VERSION 5.7 ;
  NOWIREEXTENSIONATPIN ON ;
  DIVIDERCHAR "/" ;
  BUSBITCHARS "[]" ;
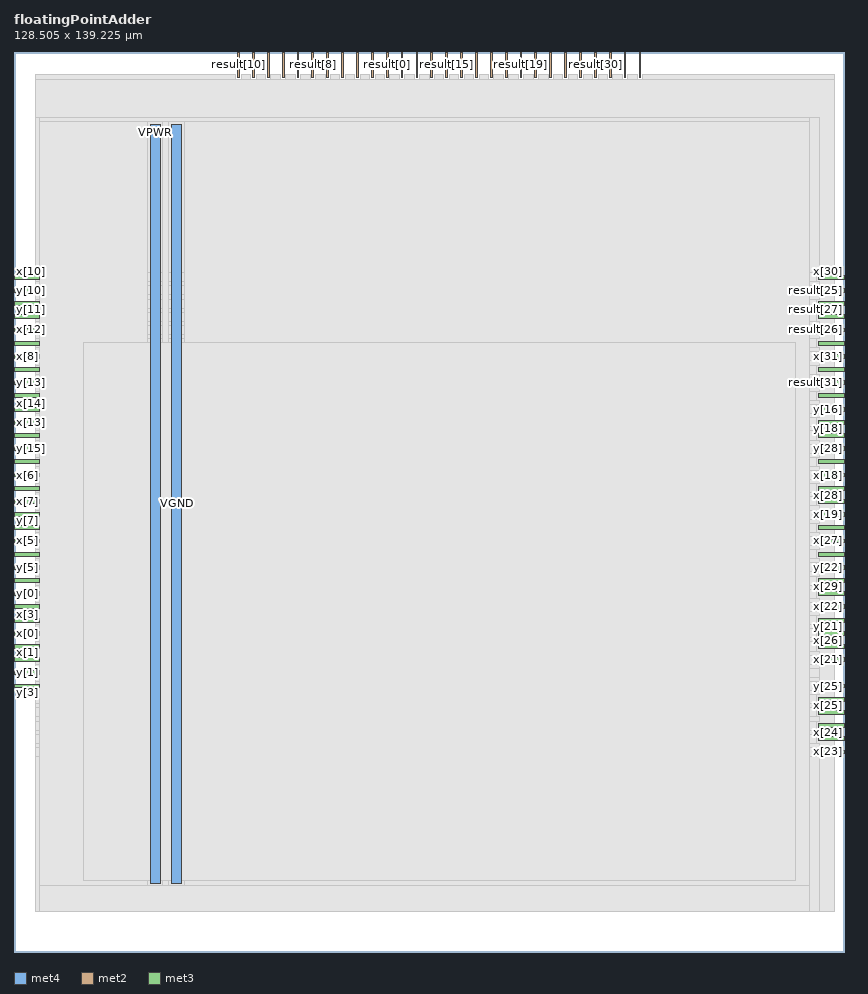
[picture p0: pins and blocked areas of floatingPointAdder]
MACRO floatingPointAdder
  CLASS BLOCK ;
  FOREIGN floatingPointAdder ;
  ORIGIN 0.000 0.000 ;
  SIZE 128.505 BY 139.225 ;
  PIN VGND
    DIRECTION INOUT ;
    USE GROUND ;
    PORT
      LAYER met4 ;
        RECT 24.340 10.640 25.940 128.080 ;
    END
  END VGND
  PIN VPWR
    DIRECTION INOUT ;
    USE POWER ;
    PORT
      LAYER met4 ;
        RECT 21.040 10.640 22.640 128.080 ;
    END
  END VPWR
  PIN result[0]
    DIRECTION OUTPUT ;
    USE SIGNAL ;
    ANTENNADIFFAREA 0.340600 ;
    PORT
      LAYER met2 ;
        RECT 57.590 135.225 57.870 139.225 ;
    END
  END result[0]
  PIN result[10]
    DIRECTION OUTPUT ;
    USE SIGNAL ;
    ANTENNADIFFAREA 0.340600 ;
    PORT
      LAYER met2 ;
        RECT 34.590 135.225 34.870 139.225 ;
    END
  END result[10]
  PIN result[11]
    DIRECTION OUTPUT ;
    USE SIGNAL ;
    ANTENNADIFFAREA 0.340600 ;
    PORT
      LAYER met2 ;
        RECT 43.790 135.225 44.070 139.225 ;
    END
  END result[11]
  PIN result[12]
    DIRECTION OUTPUT ;
    USE SIGNAL ;
    ANTENNADIFFAREA 0.340600 ;
    PORT
      LAYER met2 ;
        RECT 55.290 135.225 55.570 139.225 ;
    END
  END result[12]
  PIN result[13]
    DIRECTION OUTPUT ;
    USE SIGNAL ;
    ANTENNADIFFAREA 0.340600 ;
    PORT
      LAYER met2 ;
        RECT 52.990 135.225 53.270 139.225 ;
    END
  END result[13]
  PIN result[14]
    DIRECTION OUTPUT ;
    USE SIGNAL ;
    ANTENNADIFFAREA 0.340600 ;
    PORT
      LAYER met2 ;
        RECT 69.090 135.225 69.370 139.225 ;
    END
  END result[14]
  PIN result[15]
    DIRECTION OUTPUT ;
    USE SIGNAL ;
    ANTENNADIFFAREA 0.340600 ;
    PORT
      LAYER met2 ;
        RECT 66.790 135.225 67.070 139.225 ;
    END
  END result[15]
  PIN result[16]
    DIRECTION OUTPUT ;
    USE SIGNAL ;
    ANTENNADIFFAREA 0.340600 ;
    PORT
      LAYER met2 ;
        RECT 87.490 135.225 87.770 139.225 ;
    END
  END result[16]
  PIN result[17]
    DIRECTION OUTPUT ;
    USE SIGNAL ;
    ANTENNADIFFAREA 0.340600 ;
    PORT
      LAYER met2 ;
        RECT 73.690 135.225 73.970 139.225 ;
    END
  END result[17]
  PIN result[18]
    DIRECTION OUTPUT ;
    USE SIGNAL ;
    ANTENNADIFFAREA 0.340600 ;
    PORT
      LAYER met2 ;
        RECT 85.190 135.225 85.470 139.225 ;
    END
  END result[18]
  PIN result[19]
    DIRECTION OUTPUT ;
    USE SIGNAL ;
    ANTENNADIFFAREA 0.340600 ;
    PORT
      LAYER met2 ;
        RECT 78.290 135.225 78.570 139.225 ;
    END
  END result[19]
  PIN result[1]
    DIRECTION OUTPUT ;
    USE SIGNAL ;
    ANTENNADIFFAREA 0.340600 ;
    PORT
      LAYER met2 ;
        RECT 64.490 135.225 64.770 139.225 ;
    END
  END result[1]
  PIN result[20]
    DIRECTION OUTPUT ;
    USE SIGNAL ;
    ANTENNADIFFAREA 0.340600 ;
    PORT
      LAYER met2 ;
        RECT 80.590 135.225 80.870 139.225 ;
    END
  END result[20]
  PIN result[21]
    DIRECTION OUTPUT ;
    USE SIGNAL ;
    ANTENNADIFFAREA 0.340600 ;
    PORT
      LAYER met2 ;
        RECT 82.890 135.225 83.170 139.225 ;
    END
  END result[21]
  PIN result[22]
    DIRECTION OUTPUT ;
    USE SIGNAL ;
    ANTENNADIFFAREA 0.340600 ;
    PORT
      LAYER met2 ;
        RECT 92.090 135.225 92.370 139.225 ;
    END
  END result[22]
  PIN result[23]
    DIRECTION OUTPUT ;
    USE SIGNAL ;
    ANTENNADIFFAREA 0.340600 ;
    PORT
      LAYER met3 ;
        RECT 124.505 93.880 128.505 94.480 ;
    END
  END result[23]
  PIN result[24]
    DIRECTION OUTPUT ;
    USE SIGNAL ;
    ANTENNADIFFAREA 0.340600 ;
    PORT
      LAYER met3 ;
        RECT 124.505 89.800 128.505 90.400 ;
    END
  END result[24]
  PIN result[25]
    DIRECTION OUTPUT ;
    USE SIGNAL ;
    ANTENNADIFFAREA 0.340600 ;
    PORT
      LAYER met3 ;
        RECT 124.505 102.040 128.505 102.640 ;
    END
  END result[25]
  PIN result[26]
    DIRECTION OUTPUT ;
    USE SIGNAL ;
    ANTENNADIFFAREA 0.340600 ;
    PORT
      LAYER met3 ;
        RECT 124.505 95.920 128.505 96.520 ;
    END
  END result[26]
  PIN result[27]
    DIRECTION OUTPUT ;
    USE SIGNAL ;
    ANTENNADIFFAREA 0.340600 ;
    PORT
      LAYER met3 ;
        RECT 124.505 100.000 128.505 100.600 ;
    END
  END result[27]
  PIN result[28]
    DIRECTION OUTPUT ;
    USE SIGNAL ;
    ANTENNADIFFAREA 0.340600 ;
    PORT
      LAYER met2 ;
        RECT 96.690 135.225 96.970 139.225 ;
    END
  END result[28]
  PIN result[29]
    DIRECTION OUTPUT ;
    USE SIGNAL ;
    ANTENNADIFFAREA 0.340600 ;
    PORT
      LAYER met2 ;
        RECT 94.390 135.225 94.670 139.225 ;
    END
  END result[29]
  PIN result[2]
    DIRECTION OUTPUT ;
    USE SIGNAL ;
    ANTENNADIFFAREA 0.340600 ;
    PORT
      LAYER met2 ;
        RECT 59.890 135.225 60.170 139.225 ;
    END
  END result[2]
  PIN result[30]
    DIRECTION OUTPUT ;
    USE SIGNAL ;
    ANTENNADIFFAREA 0.340600 ;
    PORT
      LAYER met2 ;
        RECT 89.790 135.225 90.070 139.225 ;
    END
  END result[30]
  PIN result[31]
    DIRECTION OUTPUT ;
    USE SIGNAL ;
    ANTENNADIFFAREA 0.340600 ;
    PORT
      LAYER met3 ;
        RECT 124.505 87.760 128.505 88.360 ;
    END
  END result[31]
  PIN result[3]
    DIRECTION OUTPUT ;
    USE SIGNAL ;
    ANTENNADIFFAREA 0.340600 ;
    PORT
      LAYER met2 ;
        RECT 36.890 135.225 37.170 139.225 ;
    END
  END result[3]
  PIN result[4]
    DIRECTION OUTPUT ;
    USE SIGNAL ;
    ANTENNADIFFAREA 0.340600 ;
    PORT
      LAYER met2 ;
        RECT 39.190 135.225 39.470 139.225 ;
    END
  END result[4]
  PIN result[5]
    DIRECTION OUTPUT ;
    USE SIGNAL ;
    ANTENNADIFFAREA 0.340600 ;
    PORT
      LAYER met2 ;
        RECT 50.690 135.225 50.970 139.225 ;
    END
  END result[5]
  PIN result[6]
    DIRECTION OUTPUT ;
    USE SIGNAL ;
    ANTENNADIFFAREA 0.340600 ;
    PORT
      LAYER met2 ;
        RECT 62.190 135.225 62.470 139.225 ;
    END
  END result[6]
  PIN result[7]
    DIRECTION OUTPUT ;
    USE SIGNAL ;
    ANTENNADIFFAREA 0.340600 ;
    PORT
      LAYER met2 ;
        RECT 48.390 135.225 48.670 139.225 ;
    END
  END result[7]
  PIN result[8]
    DIRECTION OUTPUT ;
    USE SIGNAL ;
    ANTENNADIFFAREA 0.340600 ;
    PORT
      LAYER met2 ;
        RECT 46.090 135.225 46.370 139.225 ;
    END
  END result[8]
  PIN result[9]
    DIRECTION OUTPUT ;
    USE SIGNAL ;
    ANTENNADIFFAREA 0.340600 ;
    PORT
      LAYER met2 ;
        RECT 41.490 135.225 41.770 139.225 ;
    END
  END result[9]
  PIN x[0]
    DIRECTION INPUT ;
    USE SIGNAL ;
    ANTENNAGATEAREA 0.196500 ;
    PORT
      LAYER met3 ;
        RECT 0.000 49.000 4.000 49.600 ;
    END
  END x[0]
  PIN x[10]
    DIRECTION INPUT ;
    USE SIGNAL ;
    ANTENNAGATEAREA 0.196500 ;
    PORT
      LAYER met3 ;
        RECT 0.000 104.080 4.000 104.680 ;
    END
  END x[10]
  PIN x[11]
    DIRECTION INPUT ;
    USE SIGNAL ;
    ANTENNAGATEAREA 0.213000 ;
    PORT
      LAYER met3 ;
        RECT 0.000 97.960 4.000 98.560 ;
    END
  END x[11]
  PIN x[12]
    DIRECTION INPUT ;
    USE SIGNAL ;
    ANTENNAGATEAREA 0.213000 ;
    PORT
      LAYER met3 ;
        RECT 0.000 95.920 4.000 96.520 ;
    END
  END x[12]
  PIN x[13]
    DIRECTION INPUT ;
    USE SIGNAL ;
    ANTENNAGATEAREA 0.196500 ;
    PORT
      LAYER met3 ;
        RECT 0.000 81.640 4.000 82.240 ;
    END
  END x[13]
  PIN x[14]
    DIRECTION INPUT ;
    USE SIGNAL ;
    ANTENNAGATEAREA 0.196500 ;
    PORT
      LAYER met3 ;
        RECT 0.000 83.680 4.000 84.280 ;
    END
  END x[14]
  PIN x[15]
    DIRECTION INPUT ;
    USE SIGNAL ;
    ANTENNAGATEAREA 0.213000 ;
    PORT
      LAYER met3 ;
        RECT 0.000 75.520 4.000 76.120 ;
    END
  END x[15]
  PIN x[16]
    DIRECTION INPUT ;
    USE SIGNAL ;
    ANTENNAGATEAREA 0.159000 ;
    PORT
      LAYER met2 ;
        RECT 71.390 135.225 71.670 139.225 ;
    END
  END x[16]
  PIN x[17]
    DIRECTION INPUT ;
    USE SIGNAL ;
    ANTENNAGATEAREA 0.631200 ;
    ANTENNADIFFAREA 0.434700 ;
    PORT
      LAYER met3 ;
        RECT 124.505 75.520 128.505 76.120 ;
    END
  END x[17]
  PIN x[18]
    DIRECTION INPUT ;
    USE SIGNAL ;
    ANTENNAGATEAREA 1.065900 ;
    ANTENNADIFFAREA 0.869400 ;
    PORT
      LAYER met3 ;
        RECT 124.505 73.480 128.505 74.080 ;
    END
  END x[18]
  PIN x[19]
    DIRECTION INPUT ;
    USE SIGNAL ;
    ANTENNAGATEAREA 0.593700 ;
    ANTENNADIFFAREA 0.434700 ;
    PORT
      LAYER met3 ;
        RECT 124.505 67.360 128.505 67.960 ;
    END
  END x[19]
  PIN x[1]
    DIRECTION INPUT ;
    USE SIGNAL ;
    ANTENNAGATEAREA 0.196500 ;
    PORT
      LAYER met3 ;
        RECT 0.000 46.960 4.000 47.560 ;
    END
  END x[1]
  PIN x[20]
    DIRECTION INPUT ;
    USE SIGNAL ;
    ANTENNAGATEAREA 0.196500 ;
    PORT
      LAYER met3 ;
        RECT 124.505 71.440 128.505 72.040 ;
    END
  END x[20]
  PIN x[21]
    DIRECTION INPUT ;
    USE SIGNAL ;
    ANTENNAGATEAREA 0.631200 ;
    ANTENNADIFFAREA 0.434700 ;
    PORT
      LAYER met3 ;
        RECT 124.505 44.920 128.505 45.520 ;
    END
  END x[21]
  PIN x[22]
    DIRECTION INPUT ;
    USE SIGNAL ;
    ANTENNAGATEAREA 0.631200 ;
    ANTENNADIFFAREA 0.434700 ;
    PORT
      LAYER met3 ;
        RECT 124.505 53.080 128.505 53.680 ;
    END
  END x[22]
  PIN x[23]
    DIRECTION INPUT ;
    USE SIGNAL ;
    ANTENNAGATEAREA 0.213000 ;
    PORT
      LAYER met3 ;
        RECT 124.505 30.640 128.505 31.240 ;
    END
  END x[23]
  PIN x[24]
    DIRECTION INPUT ;
    USE SIGNAL ;
    ANTENNAGATEAREA 0.159000 ;
    PORT
      LAYER met3 ;
        RECT 124.505 32.680 128.505 33.280 ;
    END
  END x[24]
  PIN x[25]
    DIRECTION INPUT ;
    USE SIGNAL ;
    ANTENNAGATEAREA 0.213000 ;
    PORT
      LAYER met3 ;
        RECT 124.505 38.800 128.505 39.400 ;
    END
  END x[25]
  PIN x[26]
    DIRECTION INPUT ;
    USE SIGNAL ;
    ANTENNAGATEAREA 0.159000 ;
    PORT
      LAYER met3 ;
        RECT 124.505 46.960 128.505 47.560 ;
    END
  END x[26]
  PIN x[27]
    DIRECTION INPUT ;
    USE SIGNAL ;
    ANTENNAGATEAREA 0.159000 ;
    PORT
      LAYER met3 ;
        RECT 124.505 63.280 128.505 63.880 ;
    END
  END x[27]
  PIN x[28]
    DIRECTION INPUT ;
    USE SIGNAL ;
    ANTENNAGATEAREA 0.213000 ;
    PORT
      LAYER met3 ;
        RECT 124.505 69.400 128.505 70.000 ;
    END
  END x[28]
  PIN x[29]
    DIRECTION INPUT ;
    USE SIGNAL ;
    ANTENNAGATEAREA 0.426000 ;
    PORT
      LAYER met3 ;
        RECT 124.505 57.160 128.505 57.760 ;
    END
  END x[29]
  PIN x[2]
    DIRECTION INPUT ;
    USE SIGNAL ;
    ANTENNAGATEAREA 0.126000 ;
    PORT
      LAYER met3 ;
        RECT 0.000 44.920 4.000 45.520 ;
    END
  END x[2]
  PIN x[30]
    DIRECTION INPUT ;
    USE SIGNAL ;
    ANTENNAGATEAREA 0.213000 ;
    PORT
      LAYER met3 ;
        RECT 124.505 104.080 128.505 104.680 ;
    END
  END x[30]
  PIN x[31]
    DIRECTION INPUT ;
    USE SIGNAL ;
    ANTENNAGATEAREA 0.213000 ;
    PORT
      LAYER met3 ;
        RECT 124.505 91.840 128.505 92.440 ;
    END
  END x[31]
  PIN x[3]
    DIRECTION INPUT ;
    USE SIGNAL ;
    ANTENNAGATEAREA 0.196500 ;
    PORT
      LAYER met3 ;
        RECT 0.000 51.040 4.000 51.640 ;
    END
  END x[3]
  PIN x[4]
    DIRECTION INPUT ;
    USE SIGNAL ;
    ANTENNAGATEAREA 0.126000 ;
    PORT
      LAYER met3 ;
        RECT 0.000 65.320 4.000 65.920 ;
    END
  END x[4]
  PIN x[5]
    DIRECTION INPUT ;
    USE SIGNAL ;
    ANTENNAGATEAREA 0.213000 ;
    PORT
      LAYER met3 ;
        RECT 0.000 63.280 4.000 63.880 ;
    END
  END x[5]
  PIN x[6]
    DIRECTION INPUT ;
    USE SIGNAL ;
    ANTENNAGATEAREA 0.213000 ;
    PORT
      LAYER met3 ;
        RECT 0.000 73.480 4.000 74.080 ;
    END
  END x[6]
  PIN x[7]
    DIRECTION INPUT ;
    USE SIGNAL ;
    ANTENNAGATEAREA 0.196500 ;
    PORT
      LAYER met3 ;
        RECT 0.000 69.400 4.000 70.000 ;
    END
  END x[7]
  PIN x[8]
    DIRECTION INPUT ;
    USE SIGNAL ;
    ANTENNAGATEAREA 0.196500 ;
    PORT
      LAYER met3 ;
        RECT 0.000 91.840 4.000 92.440 ;
    END
  END x[8]
  PIN x[9]
    DIRECTION INPUT ;
    USE SIGNAL ;
    ANTENNAGATEAREA 0.196500 ;
    PORT
      LAYER met3 ;
        RECT 0.000 93.880 4.000 94.480 ;
    END
  END x[9]
  PIN y[0]
    DIRECTION INPUT ;
    USE SIGNAL ;
    ANTENNAGATEAREA 0.126000 ;
    PORT
      LAYER met3 ;
        RECT 0.000 55.120 4.000 55.720 ;
    END
  END y[0]
  PIN y[10]
    DIRECTION INPUT ;
    USE SIGNAL ;
    ANTENNAGATEAREA 0.126000 ;
    PORT
      LAYER met3 ;
        RECT 0.000 102.040 4.000 102.640 ;
    END
  END y[10]
  PIN y[11]
    DIRECTION INPUT ;
    USE SIGNAL ;
    ANTENNAGATEAREA 0.126000 ;
    PORT
      LAYER met3 ;
        RECT 0.000 100.000 4.000 100.600 ;
    END
  END y[11]
  PIN y[12]
    DIRECTION INPUT ;
    USE SIGNAL ;
    ANTENNAGATEAREA 0.213000 ;
    PORT
      LAYER met3 ;
        RECT 0.000 79.600 4.000 80.200 ;
    END
  END y[12]
  PIN y[13]
    DIRECTION INPUT ;
    USE SIGNAL ;
    ANTENNAGATEAREA 0.126000 ;
    PORT
      LAYER met3 ;
        RECT 0.000 87.760 4.000 88.360 ;
    END
  END y[13]
  PIN y[14]
    DIRECTION INPUT ;
    USE SIGNAL ;
    ANTENNAGATEAREA 0.196500 ;
    PORT
      LAYER met3 ;
        RECT 0.000 85.720 4.000 86.320 ;
    END
  END y[14]
  PIN y[15]
    DIRECTION INPUT ;
    USE SIGNAL ;
    ANTENNAGATEAREA 0.213000 ;
    PORT
      LAYER met3 ;
        RECT 0.000 77.560 4.000 78.160 ;
    END
  END y[15]
  PIN y[16]
    DIRECTION INPUT ;
    USE SIGNAL ;
    ANTENNAGATEAREA 0.213000 ;
    PORT
      LAYER met3 ;
        RECT 124.505 83.680 128.505 84.280 ;
    END
  END y[16]
  PIN y[17]
    DIRECTION INPUT ;
    USE SIGNAL ;
    ANTENNAGATEAREA 0.159000 ;
    PORT
      LAYER met2 ;
        RECT 75.990 135.225 76.270 139.225 ;
    END
  END y[17]
  PIN y[18]
    DIRECTION INPUT ;
    USE SIGNAL ;
    ANTENNAGATEAREA 0.159000 ;
    PORT
      LAYER met3 ;
        RECT 124.505 81.640 128.505 82.240 ;
    END
  END y[18]
  PIN y[19]
    DIRECTION INPUT ;
    USE SIGNAL ;
    ANTENNAGATEAREA 0.213000 ;
    PORT
      LAYER met3 ;
        RECT 124.505 65.320 128.505 65.920 ;
    END
  END y[19]
  PIN y[1]
    DIRECTION INPUT ;
    USE SIGNAL ;
    ANTENNAGATEAREA 0.213000 ;
    PORT
      LAYER met3 ;
        RECT 0.000 42.880 4.000 43.480 ;
    END
  END y[1]
  PIN y[20]
    DIRECTION INPUT ;
    USE SIGNAL ;
    ANTENNAGATEAREA 0.213000 ;
    PORT
      LAYER met3 ;
        RECT 124.505 79.600 128.505 80.200 ;
    END
  END y[20]
  PIN y[21]
    DIRECTION INPUT ;
    USE SIGNAL ;
    ANTENNAGATEAREA 0.159000 ;
    PORT
      LAYER met3 ;
        RECT 124.505 51.040 128.505 51.640 ;
    END
  END y[21]
  PIN y[22]
    DIRECTION INPUT ;
    USE SIGNAL ;
    ANTENNAGATEAREA 0.213000 ;
    PORT
      LAYER met3 ;
        RECT 124.505 59.200 128.505 59.800 ;
    END
  END y[22]
  PIN y[23]
    DIRECTION INPUT ;
    USE SIGNAL ;
    ANTENNAGATEAREA 0.213000 ;
    PORT
      LAYER met3 ;
        RECT 124.505 34.720 128.505 35.320 ;
    END
  END y[23]
  PIN y[24]
    DIRECTION INPUT ;
    USE SIGNAL ;
    ANTENNAGATEAREA 0.213000 ;
    PORT
      LAYER met3 ;
        RECT 124.505 36.760 128.505 37.360 ;
    END
  END y[24]
  PIN y[25]
    DIRECTION INPUT ;
    USE SIGNAL ;
    ANTENNAGATEAREA 0.247500 ;
    PORT
      LAYER met3 ;
        RECT 124.505 40.840 128.505 41.440 ;
    END
  END y[25]
  PIN y[26]
    DIRECTION INPUT ;
    USE SIGNAL ;
    ANTENNAGATEAREA 0.213000 ;
    PORT
      LAYER met3 ;
        RECT 124.505 49.000 128.505 49.600 ;
    END
  END y[26]
  PIN y[27]
    DIRECTION INPUT ;
    USE SIGNAL ;
    ANTENNAGATEAREA 0.213000 ;
    PORT
      LAYER met3 ;
        RECT 124.505 61.240 128.505 61.840 ;
    END
  END y[27]
  PIN y[28]
    DIRECTION INPUT ;
    USE SIGNAL ;
    ANTENNAGATEAREA 0.213000 ;
    PORT
      LAYER met3 ;
        RECT 124.505 77.560 128.505 78.160 ;
    END
  END y[28]
  PIN y[29]
    DIRECTION INPUT ;
    USE SIGNAL ;
    ANTENNAGATEAREA 0.213000 ;
    PORT
      LAYER met3 ;
        RECT 124.505 55.120 128.505 55.720 ;
    END
  END y[29]
  PIN y[2]
    DIRECTION INPUT ;
    USE SIGNAL ;
    ANTENNAGATEAREA 0.213000 ;
    PORT
      LAYER met3 ;
        RECT 0.000 53.080 4.000 53.680 ;
    END
  END y[2]
  PIN y[30]
    DIRECTION INPUT ;
    USE SIGNAL ;
    ANTENNAGATEAREA 0.213000 ;
    PORT
      LAYER met3 ;
        RECT 124.505 97.960 128.505 98.560 ;
    END
  END y[30]
  PIN y[31]
    DIRECTION INPUT ;
    USE SIGNAL ;
    ANTENNAGATEAREA 0.213000 ;
    PORT
      LAYER met3 ;
        RECT 124.505 85.720 128.505 86.320 ;
    END
  END y[31]
  PIN y[3]
    DIRECTION INPUT ;
    USE SIGNAL ;
    ANTENNAGATEAREA 0.196500 ;
    PORT
      LAYER met3 ;
        RECT 0.000 40.840 4.000 41.440 ;
    END
  END y[3]
  PIN y[4]
    DIRECTION INPUT ;
    USE SIGNAL ;
    ANTENNAGATEAREA 0.213000 ;
    PORT
      LAYER met3 ;
        RECT 0.000 57.160 4.000 57.760 ;
    END
  END y[4]
  PIN y[5]
    DIRECTION INPUT ;
    USE SIGNAL ;
    ANTENNAGATEAREA 0.126000 ;
    PORT
      LAYER met3 ;
        RECT 0.000 59.200 4.000 59.800 ;
    END
  END y[5]
  PIN y[6]
    DIRECTION INPUT ;
    USE SIGNAL ;
    ANTENNAGATEAREA 0.196500 ;
    PORT
      LAYER met3 ;
        RECT 0.000 71.440 4.000 72.040 ;
    END
  END y[6]
  PIN y[7]
    DIRECTION INPUT ;
    USE SIGNAL ;
    ANTENNAGATEAREA 0.213000 ;
    PORT
      LAYER met3 ;
        RECT 0.000 67.360 4.000 67.960 ;
    END
  END y[7]
  PIN y[8]
    DIRECTION INPUT ;
    USE SIGNAL ;
    ANTENNAGATEAREA 0.126000 ;
    PORT
      LAYER met3 ;
        RECT 0.000 89.800 4.000 90.400 ;
    END
  END y[8]
  PIN y[9]
    DIRECTION INPUT ;
    USE SIGNAL ;
    ANTENNAGATEAREA 0.213000 ;
    PORT
      LAYER met3 ;
        RECT 0.000 61.240 4.000 61.840 ;
    END
  END y[9]
  OBS
      LAYER nwell ;
        RECT 5.330 10.795 123.010 128.030 ;
      LAYER li1 ;
        RECT 5.520 10.795 122.820 127.925 ;
      LAYER met1 ;
        RECT 3.290 9.560 126.890 132.220 ;
      LAYER met2 ;
        RECT 3.310 134.945 34.310 135.730 ;
        RECT 35.150 134.945 36.610 135.730 ;
        RECT 37.450 134.945 38.910 135.730 ;
        RECT 39.750 134.945 41.210 135.730 ;
        RECT 42.050 134.945 43.510 135.730 ;
        RECT 44.350 134.945 45.810 135.730 ;
        RECT 46.650 134.945 48.110 135.730 ;
        RECT 48.950 134.945 50.410 135.730 ;
        RECT 51.250 134.945 52.710 135.730 ;
        RECT 53.550 134.945 55.010 135.730 ;
        RECT 55.850 134.945 57.310 135.730 ;
        RECT 58.150 134.945 59.610 135.730 ;
        RECT 60.450 134.945 61.910 135.730 ;
        RECT 62.750 134.945 64.210 135.730 ;
        RECT 65.050 134.945 66.510 135.730 ;
        RECT 67.350 134.945 68.810 135.730 ;
        RECT 69.650 134.945 71.110 135.730 ;
        RECT 71.950 134.945 73.410 135.730 ;
        RECT 74.250 134.945 75.710 135.730 ;
        RECT 76.550 134.945 78.010 135.730 ;
        RECT 78.850 134.945 80.310 135.730 ;
        RECT 81.150 134.945 82.610 135.730 ;
        RECT 83.450 134.945 84.910 135.730 ;
        RECT 85.750 134.945 87.210 135.730 ;
        RECT 88.050 134.945 89.510 135.730 ;
        RECT 90.350 134.945 91.810 135.730 ;
        RECT 92.650 134.945 94.110 135.730 ;
        RECT 94.950 134.945 96.410 135.730 ;
        RECT 97.250 134.945 126.860 135.730 ;
        RECT 3.310 6.275 126.860 134.945 ;
      LAYER met3 ;
        RECT 3.285 105.080 124.595 129.025 ;
        RECT 4.400 103.680 124.105 105.080 ;
        RECT 3.285 103.040 124.595 103.680 ;
        RECT 4.400 101.640 124.105 103.040 ;
        RECT 3.285 101.000 124.595 101.640 ;
        RECT 4.400 99.600 124.105 101.000 ;
        RECT 3.285 98.960 124.595 99.600 ;
        RECT 4.400 97.560 124.105 98.960 ;
        RECT 3.285 96.920 124.595 97.560 ;
        RECT 4.400 95.520 124.105 96.920 ;
        RECT 3.285 94.880 124.595 95.520 ;
        RECT 4.400 93.480 124.105 94.880 ;
        RECT 3.285 92.840 124.595 93.480 ;
        RECT 4.400 91.440 124.105 92.840 ;
        RECT 3.285 90.800 124.595 91.440 ;
        RECT 4.400 89.400 124.105 90.800 ;
        RECT 3.285 88.760 124.595 89.400 ;
        RECT 4.400 87.360 124.105 88.760 ;
        RECT 3.285 86.720 124.595 87.360 ;
        RECT 4.400 85.320 124.105 86.720 ;
        RECT 3.285 84.680 124.595 85.320 ;
        RECT 4.400 83.280 124.105 84.680 ;
        RECT 3.285 82.640 124.595 83.280 ;
        RECT 4.400 81.240 124.105 82.640 ;
        RECT 3.285 80.600 124.595 81.240 ;
        RECT 4.400 79.200 124.105 80.600 ;
        RECT 3.285 78.560 124.595 79.200 ;
        RECT 4.400 77.160 124.105 78.560 ;
        RECT 3.285 76.520 124.595 77.160 ;
        RECT 4.400 75.120 124.105 76.520 ;
        RECT 3.285 74.480 124.595 75.120 ;
        RECT 4.400 73.080 124.105 74.480 ;
        RECT 3.285 72.440 124.595 73.080 ;
        RECT 4.400 71.040 124.105 72.440 ;
        RECT 3.285 70.400 124.595 71.040 ;
        RECT 4.400 69.000 124.105 70.400 ;
        RECT 3.285 68.360 124.595 69.000 ;
        RECT 4.400 66.960 124.105 68.360 ;
        RECT 3.285 66.320 124.595 66.960 ;
        RECT 4.400 64.920 124.105 66.320 ;
        RECT 3.285 64.280 124.595 64.920 ;
        RECT 4.400 62.880 124.105 64.280 ;
        RECT 3.285 62.240 124.595 62.880 ;
        RECT 4.400 60.840 124.105 62.240 ;
        RECT 3.285 60.200 124.595 60.840 ;
        RECT 4.400 58.800 124.105 60.200 ;
        RECT 3.285 58.160 124.595 58.800 ;
        RECT 4.400 56.760 124.105 58.160 ;
        RECT 3.285 56.120 124.595 56.760 ;
        RECT 4.400 54.720 124.105 56.120 ;
        RECT 3.285 54.080 124.595 54.720 ;
        RECT 4.400 52.680 124.105 54.080 ;
        RECT 3.285 52.040 124.595 52.680 ;
        RECT 4.400 50.640 124.105 52.040 ;
        RECT 3.285 50.000 124.595 50.640 ;
        RECT 4.400 48.600 124.105 50.000 ;
        RECT 3.285 47.960 124.595 48.600 ;
        RECT 4.400 46.560 124.105 47.960 ;
        RECT 3.285 45.920 124.595 46.560 ;
        RECT 4.400 44.520 124.105 45.920 ;
        RECT 3.285 43.880 124.595 44.520 ;
        RECT 4.400 42.480 124.595 43.880 ;
        RECT 3.285 41.840 124.595 42.480 ;
        RECT 4.400 40.440 124.105 41.840 ;
        RECT 3.285 39.800 124.595 40.440 ;
        RECT 3.285 38.400 124.105 39.800 ;
        RECT 3.285 37.760 124.595 38.400 ;
        RECT 3.285 36.360 124.105 37.760 ;
        RECT 3.285 35.720 124.595 36.360 ;
        RECT 3.285 34.320 124.105 35.720 ;
        RECT 3.285 33.680 124.595 34.320 ;
        RECT 3.285 32.280 124.105 33.680 ;
        RECT 3.285 31.640 124.595 32.280 ;
        RECT 3.285 30.240 124.105 31.640 ;
        RECT 3.285 6.295 124.595 30.240 ;
      LAYER met4 ;
        RECT 3.975 128.480 122.985 129.025 ;
        RECT 3.975 10.240 20.640 128.480 ;
        RECT 23.040 10.240 23.940 128.480 ;
        RECT 26.340 10.240 122.985 128.480 ;
        RECT 3.975 6.295 122.985 10.240 ;
      LAYER met5 ;
        RECT 10.700 11.100 120.860 94.300 ;
  END
END floatingPointAdder
END LIBRARY

